VERSION 5.7 ;
  NOWIREEXTENSIONATPIN ON ;
  DIVIDERCHAR "/" ;
  BUSBITCHARS "[]" ;
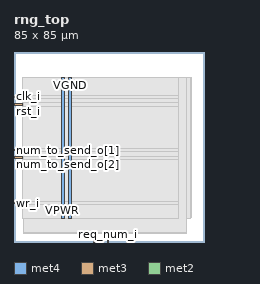
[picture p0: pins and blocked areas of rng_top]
MACRO rng_top
  CLASS BLOCK ;
  FOREIGN rng_top ;
  ORIGIN 0.000 0.000 ;
  SIZE 85.000 BY 85.000 ;
  PIN VGND
    DIRECTION INOUT ;
    USE GROUND ;
    PORT
      LAYER met4 ;
        RECT 24.340 10.640 25.940 73.680 ;
    END
  END VGND
  PIN VPWR
    DIRECTION INOUT ;
    USE POWER ;
    PORT
      LAYER met4 ;
        RECT 21.040 10.640 22.640 73.680 ;
    END
  END VPWR
  PIN clk_i
    DIRECTION INPUT ;
    USE SIGNAL ;
    ANTENNAGATEAREA 0.852000 ;
    PORT
      LAYER met3 ;
        RECT 0.000 64.640 4.000 65.240 ;
    END
  END clk_i
  PIN num_to_send_o[0]
    DIRECTION OUTPUT ;
    USE SIGNAL ;
    ANTENNADIFFAREA 0.445500 ;
    PORT
      LAYER met2 ;
        RECT 35.510 0.000 35.790 4.000 ;
    END
  END num_to_send_o[0]
  PIN num_to_send_o[1]
    DIRECTION OUTPUT ;
    USE SIGNAL ;
    ANTENNADIFFAREA 0.445500 ;
    PORT
      LAYER met3 ;
        RECT 0.000 40.840 4.000 41.440 ;
    END
  END num_to_send_o[1]
  PIN num_to_send_o[2]
    DIRECTION OUTPUT ;
    USE SIGNAL ;
    ANTENNADIFFAREA 0.445500 ;
    PORT
      LAYER met3 ;
        RECT 0.000 37.440 4.000 38.040 ;
    END
  END num_to_send_o[2]
  PIN req_num_i
    DIRECTION INPUT ;
    USE SIGNAL ;
    ANTENNAGATEAREA 0.196500 ;
    PORT
      LAYER met2 ;
        RECT 41.950 0.000 42.230 4.000 ;
    END
  END req_num_i
  PIN rst_i
    DIRECTION INPUT ;
    USE SIGNAL ;
    ANTENNAGATEAREA 0.196500 ;
    PORT
      LAYER met3 ;
        RECT 0.000 61.240 4.000 61.840 ;
    END
  END rst_i
  PIN wr_i
    DIRECTION INPUT ;
    USE SIGNAL ;
    ANTENNAGATEAREA 0.196500 ;
    PORT
      LAYER met3 ;
        RECT 0.000 17.040 4.000 17.640 ;
    END
  END wr_i
  OBS
      LAYER nwell ;
        RECT 5.330 10.760 79.310 73.630 ;
      LAYER li1 ;
        RECT 5.520 10.795 79.120 73.525 ;
      LAYER met1 ;
        RECT 4.210 10.640 79.120 73.680 ;
      LAYER met2 ;
        RECT 4.230 4.280 77.180 73.625 ;
        RECT 4.230 4.000 35.230 4.280 ;
        RECT 36.070 4.000 41.670 4.280 ;
        RECT 42.510 4.000 77.180 4.280 ;
      LAYER met3 ;
        RECT 3.990 65.640 73.535 73.605 ;
        RECT 4.400 64.240 73.535 65.640 ;
        RECT 3.990 62.240 73.535 64.240 ;
        RECT 4.400 60.840 73.535 62.240 ;
        RECT 3.990 41.840 73.535 60.840 ;
        RECT 4.400 40.440 73.535 41.840 ;
        RECT 3.990 38.440 73.535 40.440 ;
        RECT 4.400 37.040 73.535 38.440 ;
        RECT 3.990 18.040 73.535 37.040 ;
        RECT 4.400 16.640 73.535 18.040 ;
        RECT 3.990 10.715 73.535 16.640 ;
  END
END rng_top
END LIBRARY

